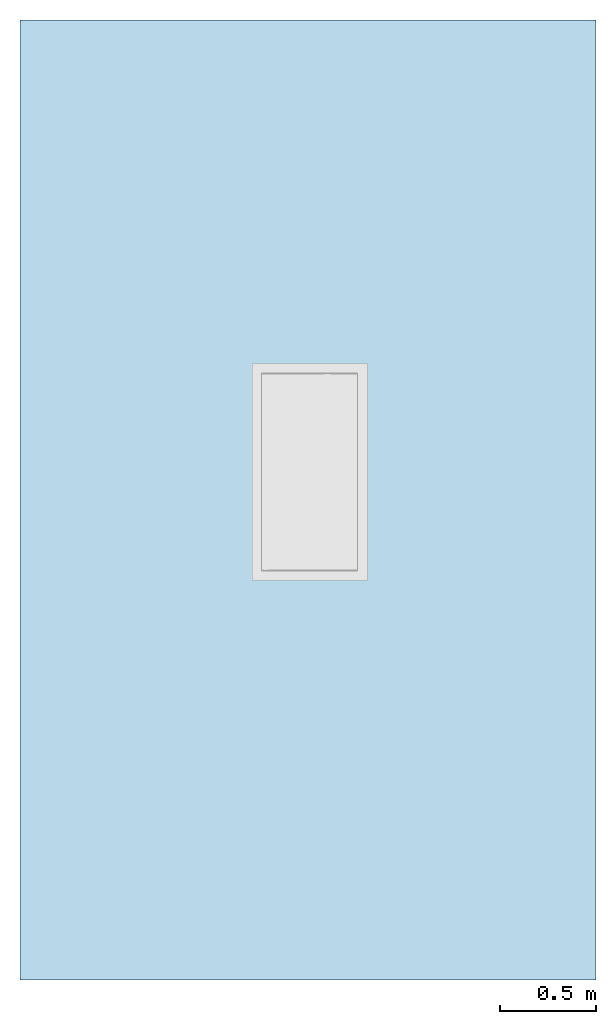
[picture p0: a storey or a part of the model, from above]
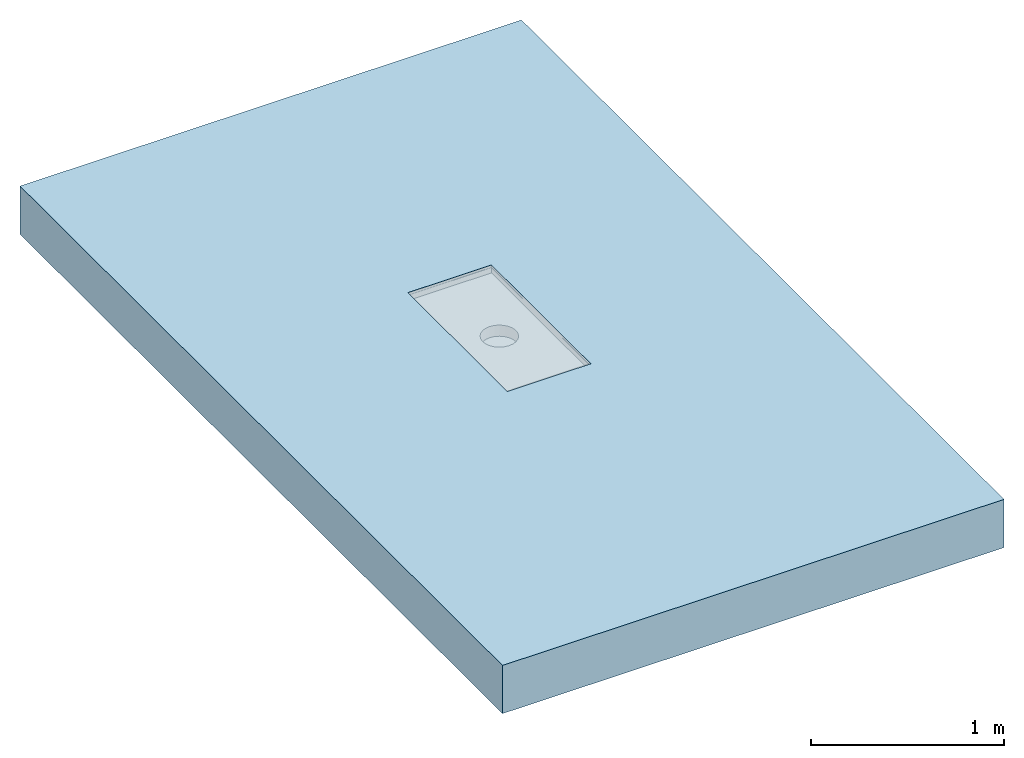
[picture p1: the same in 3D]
Properties of the parts of a building model (IFC2X3)

# File
Description: ViewDefinition [CoordinationView]
File name: Project Number
Time: 2016-11-22T10:05:06
Written by: The EXPRESS Data Manager Version 5.01.0100.02.64mod : 6 Jun 2012
Made in: 20130308_1515(x64) - Exporter 2014.0.2013.0308 - Default UI
Comment: STEP Physical File produced by: The EXPRESS Data Manager Version 5.01.0100.02.64mod : 6 Jun 2012 * Module: EDMstepFileFactory/EDMstandAlone * Creation date: Tue Nov 22 10:05:06 2016 * Host: IN-BLR-PC-0012 * Database: C:\Users\pakumar\AppData\Local\Temp\{5785CC01-1DF2-4BA7-A6E2-6FB7414CD5F8}\ifc * Database version: 5507 * Database creation date: Tue Nov 22 10:05:05 2016 * Schema: IFC2X3 * Model: DataRepository.ifc * Model creation date: Tue Nov 22 10:05:05 2016 * Header model: DataRepository.ifc_HeaderModel * Header model creation date: Tue Nov 22 10:05:05 2016 * EDMuser: sdai-user * EDMgroup: sdai-group * License ID and type: 5605 : Permanent license. Expiry date: * EDMstepFileFactory options: 020000

# IfcProject, Project Number
LongName: Project Name; Phase: Project Status

# IfcSite, Default
RefLatitude: 42, 21, 30, 344238; RefLongitude: -71, -3, -35, -194702; RefElevation: 0 mm

# IfcBuilding
Pset_BuildingCommon - NumberOfStoreys: 1
Other - Project Issue Date: Issue Date; Project Number: Project Number; Project Name: Project Name; Client Name: Owner; Project Address: Enter address here; Project Status: Project Status

# IfcBuildingStorey, Level 1
LongName: Level 1; Elevation: 0 mm
Graphics - Color: 0; Line Weight: 1; Symbol at End 1 Default: no; Line Pattern: Grid Line 1/2"; Symbol at End 2 Default: yes; Symbol: Level Head - Circle: Level Head - Circle
Constraints - Elevation Base: Project Base Point; Elevation: 0 mm
Dimensions - Computation Height: 0 mm
Identity Data - Building Story: yes; Name: Level 1; Structural: no

# IfcFlowTerminal: 416755 - Hygienic Extended Channel - with Gully 218 - 1000mm LG - 500mm Wide, ACO Tray Channel - Hygienic - Extended - 500mm Wide:416755 - Hygienic Extended Channel - with Gully 218 - 1000mm LG - 500mm Wide:445298
In: Level 1
Material: Stainless Steel AISI 304, Stainless Steel AISI 304 - Grating
Construction - Grating: yes; Detail - Outlet 200: yes; Detail - Outlet 142mm: no; 416874 - 468 x 398mm - Mesh Grating - L15 - Stainless Steel 1.4301: no; 416830 - 468 x 398mm - Ladder Grating - R50 - Stainless Steel 1.4301: no; 416828 - 468 x 499mm - Ladder Grating - R50 - Stainless Steel 1.4301: no; 416832 - 468 x 499mm - Ladder Grating - M125 - Stainless Steel 1.4301: no; 416872 - 468 x 499mm - Mesh Grating - L15 - Stainless Steel 1.4301: yes; 416892 - 468 x 499mm - Mesh Grating - L15 - Stainless Steel 1.4301: no; 416894 - 468 x 398mm - Mesh Grating - L15 - Stainless Steel 1.4301: no; 416834 - 468 x 398mm - Ladder Grating - M125 - Stainless Steel 1.4301: no
Mechanical - System Classification: Sanitary
Identity Data - Mark: 32; Address: ACO Business Centre, Caxton Road, Bedford, MK41 0LF; Watermarked By: www.acobd.com; Watermarked With: BIM Manager Premium Suite.; Website: www.acobd.com; E-mail Technical: abdtechnical@aco.co.uk; Watermark1: This file is the property of ACO Technologies PLC.; Watermark2: This file is water marked and users are prohibited to reproduce, adapt, distribute this information.; E-mail Sales: abdcommercial@aco.co.uk; Fax: +44 (0)1462 851490; Telephone: +44 (0)1462 816666; Cost: 0; Manufacturer: ACO Building Drainage
Constraints - Level: Level: Level 1
Phasing - Phase Created: New Construction
Pset_ManufacturerTypeInformation - Manufacturer: ACO Building Drainage
Dimensions - Outlet: 200 mm; Outside Outlet Rad: 100 mm; Grating Void Cut Length: 500 mm; Grating Length: 298 mm; Grating Height: 21 mm; End Plate: 1000 mm; Endplate Position: 1000 mm; Number of gratings: 2; Spigot Distance: 500 mm; Inside Outlet Rad: 98 mm; Depth: 29 mm; End Connection Plate End: -1000 mm; End Connection Plate Start: -970 mm; x: -1015 mm; Invert Depth: 50 mm; Length Channel: -970 mm; Floor Cut Void Height: 62.8 mm
General - Product Code: 416755; Weight (Kg): 10.9; Channel Dimension: 500 x 1030; Foul air trap seal Material: NBR; Price: POA - contact ACO; Product Type: Extended Kitchen Tray Channel; Product Description: ACO Hygiene First Extended Kitchen Tray Channel 500 x 1030 / 200 Dia Outlet & Foul Air Trap; Load Class: A15 - C250 (EN 1253); Channel Material: Stainless steel 1.4301 (EN 10088); Installation guidelines: http://issuu.com/acobuildingdrainage/docs/aco_hygiene_first_catalogue/17?e=0; Foul air trap Recyclable: Fully recyclable; Channel Colour: passivated stainless steel surface ( matt grey); Outlet Diameter (mm): 200; Maintenance guidelines: http://issuu.com/acobuildingdrainage/docs/aco_hygiene_first_catalogue/17?e=0; Channel Recycled material content: 20 - 30 %; Product Range: ACO Hygiene First; Foul air trap Recycled material content: 0%; Product Standard: EN 1253 / EN 1672 / EN ISO 14159; Channel Recyclable: Fully recyclable; Foul air trap seal Colour: Black
Model Properties - Grating Product Code 416894: N/A; Grating Product Code 416828: Load Class R 50 (EN 1253) - Ladder Grate - Stainless steel 1.4301 (EN 10088) - 468 x 499 - 12.5kg; Grating Product Code 416830: N/A; Grating Product Code 416832: Load Class M 125 (EN 1253) - Ladder Grate - Stainless steel 1.4301 (EN 10088) - 468 x 499 - 17kg; Grating Product Code 416834: N/A; Grating Product Code 416874: N/A; Grating Product Code 416892: Load Class L 15 (EN 1253) - Mesh Grate - Stainless steel 1.4301 (EN 10088) - 468 x 499 - 6.4kg; Grating Product Code 416872: Load Class L 15 (EN 1253) - Mesh Grate - Stainless steel 1.4301 (EN 10088) - 468 x 499 - 6.2kg
Other - Spigot Outlets Channels: yes; Hygienic Standard Channel - 500mm LG - 500mm Wide: no; Invert Depth Detail: 51.5 mm; Hygienic Standard Channel - 1000mm LG - 500mm Wide: yes; Number mesh: 21; Hygienic Standard Channel - 800mm LG - 500mm Wide: no; Flow: 0.155385 m3/s

# IfcOpeningElement: Recess
In: Level 1
Constraints - Level: Level: Level 1; Room Bounding: yes; Height Offset From Level: 0 mm; Related to Mass: no
Dimensions - Thickness: 304.8 mm; Volume: 160.463 ft3; Area: 161.459 ft2; Perimeter: 16000 mm
Phasing - Phase Created: New Construction
Structural - Structural: no; Enable Analytical Model: no
Identity Data - Assembly Description: Floor Construction; Assembly Code: B1010
Construction - Function: Interior; Default Thickness: 304.8 mm
Graphics - Coarse Scale Fill Color: 0
Analytical Properties - Roughness: 3; Absorptance: 0.7

# IfcSlab: Floor:Generic - 12", Floor:Generic - 12":184145
In: Level 1
PredefinedType: FLOOR; Material: Default Floor 304.8 mm
Constraints - Level: Level: Level 1; Room Bounding: yes; Height Offset From Level: 0 mm; Related to Mass: no
Dimensions - Thickness: 304.8 mm; Volume: 160.463 ft3; Area: 161.459 ft2; Perimeter: 16000 mm
Phasing - Phase Created: New Construction
Structural - Structural: no; Enable Analytical Model: no
Pset_SlabCommon - Reference: Generic - 12"; IsExternal: no; LoadBearing: yes
Identity Data - Assembly Description: Floor Construction; Assembly Code: B1010
Construction - Function: Interior; Default Thickness: 304.8 mm
Graphics - Coarse Scale Fill Color: 0
Analytical Properties - Roughness: 3; Absorptance: 0.7
